VERSION 5.8 ;
DIVIDERCHAR "/" ;
BUSBITCHARS "[]" ;

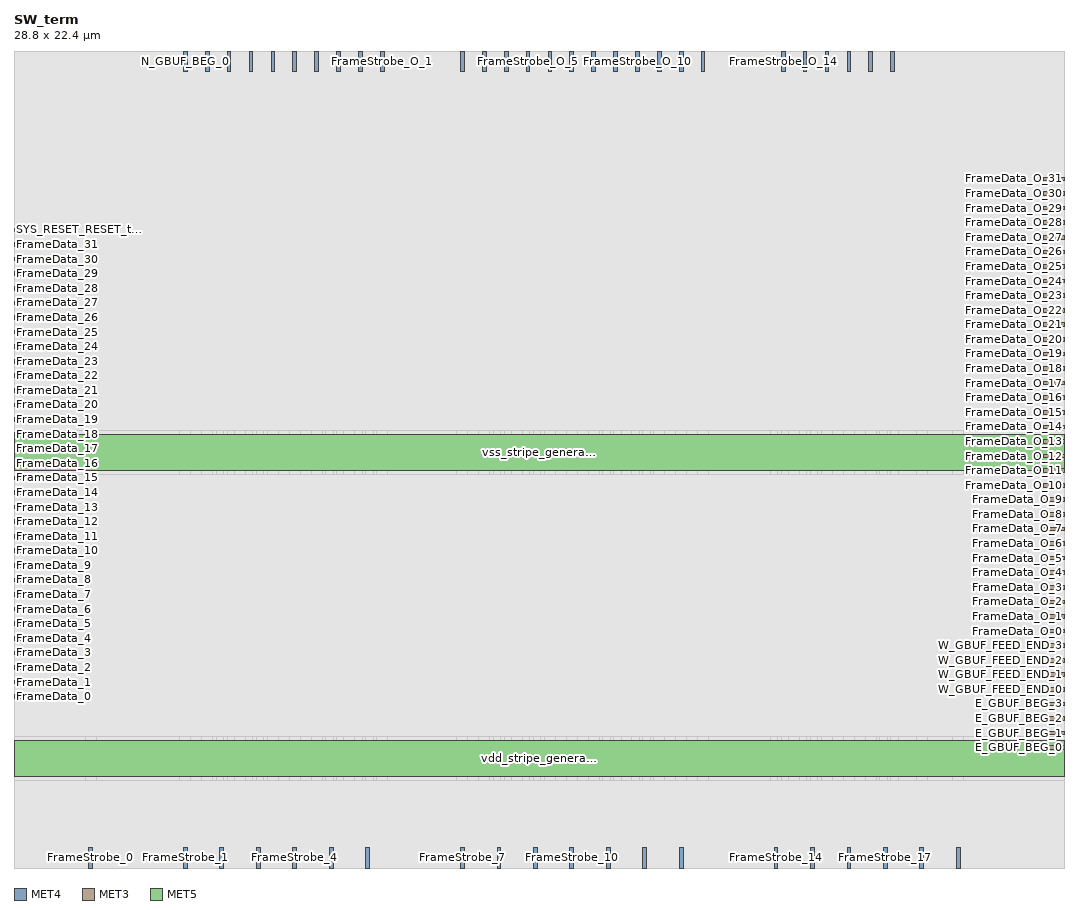
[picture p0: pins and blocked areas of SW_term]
MACRO SW_term
  CLASS BLOCK ;
  FOREIGN SW_term ;
  ORIGIN 0.0 0.0 ;
  SIZE 28.800 BY 22.400 ;
  SYMMETRY X Y ;
  PIN S_GBUF_FEED_END_0
    DIRECTION INPUT ;
    USE SIGNAL ;
    PORT
      LAYER MET4 ;
        RECT 7.050 21.850 7.150 22.400 ;
    END
  END S_GBUF_FEED_END_0
  PIN S_GBUF_FEED_END_1
    DIRECTION INPUT ;
    USE SIGNAL ;
    PORT
      LAYER MET4 ;
        RECT 7.650 21.850 7.750 22.400 ;
    END
  END S_GBUF_FEED_END_1
  PIN S_GBUF_FEED_END_2
    DIRECTION INPUT ;
    USE SIGNAL ;
    PORT
      LAYER MET4 ;
        RECT 8.250 21.850 8.350 22.400 ;
    END
  END S_GBUF_FEED_END_2
  PIN S_GBUF_FEED_END_3
    DIRECTION INPUT ;
    USE SIGNAL ;
    PORT
      LAYER MET4 ;
        RECT 8.850 21.850 8.950 22.400 ;
    END
  END S_GBUF_FEED_END_3
  PIN N_GBUF_BEG_0
    DIRECTION OUTPUT ;
    USE SIGNAL ;
    PORT
      LAYER MET4 ;
        RECT 4.650 21.850 4.750 22.400 ;
    END
  END N_GBUF_BEG_0
  PIN N_GBUF_BEG_1
    DIRECTION OUTPUT ;
    USE SIGNAL ;
    PORT
      LAYER MET4 ;
        RECT 5.250 21.850 5.350 22.400 ;
    END
  END N_GBUF_BEG_1
  PIN N_GBUF_BEG_2
    DIRECTION OUTPUT ;
    USE SIGNAL ;
    PORT
      LAYER MET4 ;
        RECT 5.850 21.850 5.950 22.400 ;
    END
  END N_GBUF_BEG_2
  PIN N_GBUF_BEG_3
    DIRECTION OUTPUT ;
    USE SIGNAL ;
    PORT
      LAYER MET4 ;
        RECT 6.450 21.850 6.550 22.400 ;
    END
  END N_GBUF_BEG_3
  PIN W_GBUF_FEED_END_0
    DIRECTION INPUT ;
    USE SIGNAL ;
    PORT
      LAYER MET3 ;
        RECT 28.250 4.850 28.800 4.950 ;
    END
  END W_GBUF_FEED_END_0
  PIN W_GBUF_FEED_END_1
    DIRECTION INPUT ;
    USE SIGNAL ;
    PORT
      LAYER MET3 ;
        RECT 28.250 5.250 28.800 5.350 ;
    END
  END W_GBUF_FEED_END_1
  PIN W_GBUF_FEED_END_2
    DIRECTION INPUT ;
    USE SIGNAL ;
    PORT
      LAYER MET3 ;
        RECT 28.250 5.650 28.800 5.750 ;
    END
  END W_GBUF_FEED_END_2
  PIN W_GBUF_FEED_END_3
    DIRECTION INPUT ;
    USE SIGNAL ;
    PORT
      LAYER MET3 ;
        RECT 28.250 6.050 28.800 6.150 ;
    END
  END W_GBUF_FEED_END_3
  PIN E_GBUF_BEG_0
    DIRECTION OUTPUT ;
    USE SIGNAL ;
    PORT
      LAYER MET3 ;
        RECT 28.250 3.250 28.800 3.350 ;
    END
  END E_GBUF_BEG_0
  PIN E_GBUF_BEG_1
    DIRECTION OUTPUT ;
    USE SIGNAL ;
    PORT
      LAYER MET3 ;
        RECT 28.250 3.650 28.800 3.750 ;
    END
  END E_GBUF_BEG_1
  PIN E_GBUF_BEG_2
    DIRECTION OUTPUT ;
    USE SIGNAL ;
    PORT
      LAYER MET3 ;
        RECT 28.250 4.050 28.800 4.150 ;
    END
  END E_GBUF_BEG_2
  PIN E_GBUF_BEG_3
    DIRECTION OUTPUT ;
    USE SIGNAL ;
    PORT
      LAYER MET3 ;
        RECT 28.250 4.450 28.800 4.550 ;
    END
  END E_GBUF_BEG_3
  PIN SYS_RESET_RESET_top
    DIRECTION INPUT ;
    USE SIGNAL ;
    PORT
      LAYER MET3 ;
        RECT 0.000 17.450 0.550 17.550 ;
    END
  END SYS_RESET_RESET_top
  PIN FrameData_0
    DIRECTION INPUT ;
    USE SIGNAL ;
    PORT
      LAYER MET3 ;
        RECT 0.000 4.650 0.550 4.750 ;
    END
  END FrameData_0
  PIN FrameData_1
    DIRECTION INPUT ;
    USE SIGNAL ;
    PORT
      LAYER MET3 ;
        RECT 0.000 5.050 0.550 5.150 ;
    END
  END FrameData_1
  PIN FrameData_2
    DIRECTION INPUT ;
    USE SIGNAL ;
    PORT
      LAYER MET3 ;
        RECT 0.000 5.450 0.550 5.550 ;
    END
  END FrameData_2
  PIN FrameData_3
    DIRECTION INPUT ;
    USE SIGNAL ;
    PORT
      LAYER MET3 ;
        RECT 0.000 5.850 0.550 5.950 ;
    END
  END FrameData_3
  PIN FrameData_4
    DIRECTION INPUT ;
    USE SIGNAL ;
    PORT
      LAYER MET3 ;
        RECT 0.000 6.250 0.550 6.350 ;
    END
  END FrameData_4
  PIN FrameData_5
    DIRECTION INPUT ;
    USE SIGNAL ;
    PORT
      LAYER MET3 ;
        RECT 0.000 6.650 0.550 6.750 ;
    END
  END FrameData_5
  PIN FrameData_6
    DIRECTION INPUT ;
    USE SIGNAL ;
    PORT
      LAYER MET3 ;
        RECT 0.000 7.050 0.550 7.150 ;
    END
  END FrameData_6
  PIN FrameData_7
    DIRECTION INPUT ;
    USE SIGNAL ;
    PORT
      LAYER MET3 ;
        RECT 0.000 7.450 0.550 7.550 ;
    END
  END FrameData_7
  PIN FrameData_8
    DIRECTION INPUT ;
    USE SIGNAL ;
    PORT
      LAYER MET3 ;
        RECT 0.000 7.850 0.550 7.950 ;
    END
  END FrameData_8
  PIN FrameData_9
    DIRECTION INPUT ;
    USE SIGNAL ;
    PORT
      LAYER MET3 ;
        RECT 0.000 8.250 0.550 8.350 ;
    END
  END FrameData_9
  PIN FrameData_10
    DIRECTION INPUT ;
    USE SIGNAL ;
    PORT
      LAYER MET3 ;
        RECT 0.000 8.650 0.550 8.750 ;
    END
  END FrameData_10
  PIN FrameData_11
    DIRECTION INPUT ;
    USE SIGNAL ;
    PORT
      LAYER MET3 ;
        RECT 0.000 9.050 0.550 9.150 ;
    END
  END FrameData_11
  PIN FrameData_12
    DIRECTION INPUT ;
    USE SIGNAL ;
    PORT
      LAYER MET3 ;
        RECT 0.000 9.450 0.550 9.550 ;
    END
  END FrameData_12
  PIN FrameData_13
    DIRECTION INPUT ;
    USE SIGNAL ;
    PORT
      LAYER MET3 ;
        RECT 0.000 9.850 0.550 9.950 ;
    END
  END FrameData_13
  PIN FrameData_14
    DIRECTION INPUT ;
    USE SIGNAL ;
    PORT
      LAYER MET3 ;
        RECT 0.000 10.250 0.550 10.350 ;
    END
  END FrameData_14
  PIN FrameData_15
    DIRECTION INPUT ;
    USE SIGNAL ;
    PORT
      LAYER MET3 ;
        RECT 0.000 10.650 0.550 10.750 ;
    END
  END FrameData_15
  PIN FrameData_16
    DIRECTION INPUT ;
    USE SIGNAL ;
    PORT
      LAYER MET3 ;
        RECT 0.000 11.050 0.550 11.150 ;
    END
  END FrameData_16
  PIN FrameData_17
    DIRECTION INPUT ;
    USE SIGNAL ;
    PORT
      LAYER MET3 ;
        RECT 0.000 11.450 0.550 11.550 ;
    END
  END FrameData_17
  PIN FrameData_18
    DIRECTION INPUT ;
    USE SIGNAL ;
    PORT
      LAYER MET3 ;
        RECT 0.000 11.850 0.550 11.950 ;
    END
  END FrameData_18
  PIN FrameData_19
    DIRECTION INPUT ;
    USE SIGNAL ;
    PORT
      LAYER MET3 ;
        RECT 0.000 12.250 0.550 12.350 ;
    END
  END FrameData_19
  PIN FrameData_20
    DIRECTION INPUT ;
    USE SIGNAL ;
    PORT
      LAYER MET3 ;
        RECT 0.000 12.650 0.550 12.750 ;
    END
  END FrameData_20
  PIN FrameData_21
    DIRECTION INPUT ;
    USE SIGNAL ;
    PORT
      LAYER MET3 ;
        RECT 0.000 13.050 0.550 13.150 ;
    END
  END FrameData_21
  PIN FrameData_22
    DIRECTION INPUT ;
    USE SIGNAL ;
    PORT
      LAYER MET3 ;
        RECT 0.000 13.450 0.550 13.550 ;
    END
  END FrameData_22
  PIN FrameData_23
    DIRECTION INPUT ;
    USE SIGNAL ;
    PORT
      LAYER MET3 ;
        RECT 0.000 13.850 0.550 13.950 ;
    END
  END FrameData_23
  PIN FrameData_24
    DIRECTION INPUT ;
    USE SIGNAL ;
    PORT
      LAYER MET3 ;
        RECT 0.000 14.250 0.550 14.350 ;
    END
  END FrameData_24
  PIN FrameData_25
    DIRECTION INPUT ;
    USE SIGNAL ;
    PORT
      LAYER MET3 ;
        RECT 0.000 14.650 0.550 14.750 ;
    END
  END FrameData_25
  PIN FrameData_26
    DIRECTION INPUT ;
    USE SIGNAL ;
    PORT
      LAYER MET3 ;
        RECT 0.000 15.050 0.550 15.150 ;
    END
  END FrameData_26
  PIN FrameData_27
    DIRECTION INPUT ;
    USE SIGNAL ;
    PORT
      LAYER MET3 ;
        RECT 0.000 15.450 0.550 15.550 ;
    END
  END FrameData_27
  PIN FrameData_28
    DIRECTION INPUT ;
    USE SIGNAL ;
    PORT
      LAYER MET3 ;
        RECT 0.000 15.850 0.550 15.950 ;
    END
  END FrameData_28
  PIN FrameData_29
    DIRECTION INPUT ;
    USE SIGNAL ;
    PORT
      LAYER MET3 ;
        RECT 0.000 16.250 0.550 16.350 ;
    END
  END FrameData_29
  PIN FrameData_30
    DIRECTION INPUT ;
    USE SIGNAL ;
    PORT
      LAYER MET3 ;
        RECT 0.000 16.650 0.550 16.750 ;
    END
  END FrameData_30
  PIN FrameData_31
    DIRECTION INPUT ;
    USE SIGNAL ;
    PORT
      LAYER MET3 ;
        RECT 0.000 17.050 0.550 17.150 ;
    END
  END FrameData_31
  PIN FrameData_O_0
    DIRECTION OUTPUT ;
    USE SIGNAL ;
    PORT
      LAYER MET3 ;
        RECT 28.250 6.450 28.800 6.550 ;
    END
  END FrameData_O_0
  PIN FrameData_O_1
    DIRECTION OUTPUT ;
    USE SIGNAL ;
    PORT
      LAYER MET3 ;
        RECT 28.250 6.850 28.800 6.950 ;
    END
  END FrameData_O_1
  PIN FrameData_O_2
    DIRECTION OUTPUT ;
    USE SIGNAL ;
    PORT
      LAYER MET3 ;
        RECT 28.250 7.250 28.800 7.350 ;
    END
  END FrameData_O_2
  PIN FrameData_O_3
    DIRECTION OUTPUT ;
    USE SIGNAL ;
    PORT
      LAYER MET3 ;
        RECT 28.250 7.650 28.800 7.750 ;
    END
  END FrameData_O_3
  PIN FrameData_O_4
    DIRECTION OUTPUT ;
    USE SIGNAL ;
    PORT
      LAYER MET3 ;
        RECT 28.250 8.050 28.800 8.150 ;
    END
  END FrameData_O_4
  PIN FrameData_O_5
    DIRECTION OUTPUT ;
    USE SIGNAL ;
    PORT
      LAYER MET3 ;
        RECT 28.250 8.450 28.800 8.550 ;
    END
  END FrameData_O_5
  PIN FrameData_O_6
    DIRECTION OUTPUT ;
    USE SIGNAL ;
    PORT
      LAYER MET3 ;
        RECT 28.250 8.850 28.800 8.950 ;
    END
  END FrameData_O_6
  PIN FrameData_O_7
    DIRECTION OUTPUT ;
    USE SIGNAL ;
    PORT
      LAYER MET3 ;
        RECT 28.250 9.250 28.800 9.350 ;
    END
  END FrameData_O_7
  PIN FrameData_O_8
    DIRECTION OUTPUT ;
    USE SIGNAL ;
    PORT
      LAYER MET3 ;
        RECT 28.250 9.650 28.800 9.750 ;
    END
  END FrameData_O_8
  PIN FrameData_O_9
    DIRECTION OUTPUT ;
    USE SIGNAL ;
    PORT
      LAYER MET3 ;
        RECT 28.250 10.050 28.800 10.150 ;
    END
  END FrameData_O_9
  PIN FrameData_O_10
    DIRECTION OUTPUT ;
    USE SIGNAL ;
    PORT
      LAYER MET3 ;
        RECT 28.250 10.450 28.800 10.550 ;
    END
  END FrameData_O_10
  PIN FrameData_O_11
    DIRECTION OUTPUT ;
    USE SIGNAL ;
    PORT
      LAYER MET3 ;
        RECT 28.250 10.850 28.800 10.950 ;
    END
  END FrameData_O_11
  PIN FrameData_O_12
    DIRECTION OUTPUT ;
    USE SIGNAL ;
    PORT
      LAYER MET3 ;
        RECT 28.250 11.250 28.800 11.350 ;
    END
  END FrameData_O_12
  PIN FrameData_O_13
    DIRECTION OUTPUT ;
    USE SIGNAL ;
    PORT
      LAYER MET3 ;
        RECT 28.250 11.650 28.800 11.750 ;
    END
  END FrameData_O_13
  PIN FrameData_O_14
    DIRECTION OUTPUT ;
    USE SIGNAL ;
    PORT
      LAYER MET3 ;
        RECT 28.250 12.050 28.800 12.150 ;
    END
  END FrameData_O_14
  PIN FrameData_O_15
    DIRECTION OUTPUT ;
    USE SIGNAL ;
    PORT
      LAYER MET3 ;
        RECT 28.250 12.450 28.800 12.550 ;
    END
  END FrameData_O_15
  PIN FrameData_O_16
    DIRECTION OUTPUT ;
    USE SIGNAL ;
    PORT
      LAYER MET3 ;
        RECT 28.250 12.850 28.800 12.950 ;
    END
  END FrameData_O_16
  PIN FrameData_O_17
    DIRECTION OUTPUT ;
    USE SIGNAL ;
    PORT
      LAYER MET3 ;
        RECT 28.250 13.250 28.800 13.350 ;
    END
  END FrameData_O_17
  PIN FrameData_O_18
    DIRECTION OUTPUT ;
    USE SIGNAL ;
    PORT
      LAYER MET3 ;
        RECT 28.250 13.650 28.800 13.750 ;
    END
  END FrameData_O_18
  PIN FrameData_O_19
    DIRECTION OUTPUT ;
    USE SIGNAL ;
    PORT
      LAYER MET3 ;
        RECT 28.250 14.050 28.800 14.150 ;
    END
  END FrameData_O_19
  PIN FrameData_O_20
    DIRECTION OUTPUT ;
    USE SIGNAL ;
    PORT
      LAYER MET3 ;
        RECT 28.250 14.450 28.800 14.550 ;
    END
  END FrameData_O_20
  PIN FrameData_O_21
    DIRECTION OUTPUT ;
    USE SIGNAL ;
    PORT
      LAYER MET3 ;
        RECT 28.250 14.850 28.800 14.950 ;
    END
  END FrameData_O_21
  PIN FrameData_O_22
    DIRECTION OUTPUT ;
    USE SIGNAL ;
    PORT
      LAYER MET3 ;
        RECT 28.250 15.250 28.800 15.350 ;
    END
  END FrameData_O_22
  PIN FrameData_O_23
    DIRECTION OUTPUT ;
    USE SIGNAL ;
    PORT
      LAYER MET3 ;
        RECT 28.250 15.650 28.800 15.750 ;
    END
  END FrameData_O_23
  PIN FrameData_O_24
    DIRECTION OUTPUT ;
    USE SIGNAL ;
    PORT
      LAYER MET3 ;
        RECT 28.250 16.050 28.800 16.150 ;
    END
  END FrameData_O_24
  PIN FrameData_O_25
    DIRECTION OUTPUT ;
    USE SIGNAL ;
    PORT
      LAYER MET3 ;
        RECT 28.250 16.450 28.800 16.550 ;
    END
  END FrameData_O_25
  PIN FrameData_O_26
    DIRECTION OUTPUT ;
    USE SIGNAL ;
    PORT
      LAYER MET3 ;
        RECT 28.250 16.850 28.800 16.950 ;
    END
  END FrameData_O_26
  PIN FrameData_O_27
    DIRECTION OUTPUT ;
    USE SIGNAL ;
    PORT
      LAYER MET3 ;
        RECT 28.250 17.250 28.800 17.350 ;
    END
  END FrameData_O_27
  PIN FrameData_O_28
    DIRECTION OUTPUT ;
    USE SIGNAL ;
    PORT
      LAYER MET3 ;
        RECT 28.250 17.650 28.800 17.750 ;
    END
  END FrameData_O_28
  PIN FrameData_O_29
    DIRECTION OUTPUT ;
    USE SIGNAL ;
    PORT
      LAYER MET3 ;
        RECT 28.250 18.050 28.800 18.150 ;
    END
  END FrameData_O_29
  PIN FrameData_O_30
    DIRECTION OUTPUT ;
    USE SIGNAL ;
    PORT
      LAYER MET3 ;
        RECT 28.250 18.450 28.800 18.550 ;
    END
  END FrameData_O_30
  PIN FrameData_O_31
    DIRECTION OUTPUT ;
    USE SIGNAL ;
    PORT
      LAYER MET3 ;
        RECT 28.250 18.850 28.800 18.950 ;
    END
  END FrameData_O_31
  PIN FrameStrobe_0
    DIRECTION INPUT ;
    USE SIGNAL ;
    PORT
      LAYER MET4 ;
        RECT 2.050 0.000 2.150 0.550 ;
    END
  END FrameStrobe_0
  PIN FrameStrobe_1
    DIRECTION INPUT ;
    USE SIGNAL ;
    PORT
      LAYER MET4 ;
        RECT 4.650 0.000 4.750 0.550 ;
    END
  END FrameStrobe_1
  PIN FrameStrobe_2
    DIRECTION INPUT ;
    USE SIGNAL ;
    PORT
      LAYER MET4 ;
        RECT 5.650 0.000 5.750 0.550 ;
    END
  END FrameStrobe_2
  PIN FrameStrobe_3
    DIRECTION INPUT ;
    USE SIGNAL ;
    PORT
      LAYER MET4 ;
        RECT 6.650 0.000 6.750 0.550 ;
    END
  END FrameStrobe_3
  PIN FrameStrobe_4
    DIRECTION INPUT ;
    USE SIGNAL ;
    PORT
      LAYER MET4 ;
        RECT 7.650 0.000 7.750 0.550 ;
    END
  END FrameStrobe_4
  PIN FrameStrobe_5
    DIRECTION INPUT ;
    USE SIGNAL ;
    PORT
      LAYER MET4 ;
        RECT 8.650 0.000 8.750 0.550 ;
    END
  END FrameStrobe_5
  PIN FrameStrobe_6
    DIRECTION INPUT ;
    USE SIGNAL ;
    PORT
      LAYER MET4 ;
        RECT 9.650 0.000 9.750 0.550 ;
    END
  END FrameStrobe_6
  PIN FrameStrobe_7
    DIRECTION INPUT ;
    USE SIGNAL ;
    PORT
      LAYER MET4 ;
        RECT 12.250 0.000 12.350 0.550 ;
    END
  END FrameStrobe_7
  PIN FrameStrobe_8
    DIRECTION INPUT ;
    USE SIGNAL ;
    PORT
      LAYER MET4 ;
        RECT 13.250 0.000 13.350 0.550 ;
    END
  END FrameStrobe_8
  PIN FrameStrobe_9
    DIRECTION INPUT ;
    USE SIGNAL ;
    PORT
      LAYER MET4 ;
        RECT 14.250 0.000 14.350 0.550 ;
    END
  END FrameStrobe_9
  PIN FrameStrobe_10
    DIRECTION INPUT ;
    USE SIGNAL ;
    PORT
      LAYER MET4 ;
        RECT 15.250 0.000 15.350 0.550 ;
    END
  END FrameStrobe_10
  PIN FrameStrobe_11
    DIRECTION INPUT ;
    USE SIGNAL ;
    PORT
      LAYER MET4 ;
        RECT 16.250 0.000 16.350 0.550 ;
    END
  END FrameStrobe_11
  PIN FrameStrobe_12
    DIRECTION INPUT ;
    USE SIGNAL ;
    PORT
      LAYER MET4 ;
        RECT 17.250 0.000 17.350 0.550 ;
    END
  END FrameStrobe_12
  PIN FrameStrobe_13
    DIRECTION INPUT ;
    USE SIGNAL ;
    PORT
      LAYER MET4 ;
        RECT 18.250 0.000 18.350 0.550 ;
    END
  END FrameStrobe_13
  PIN FrameStrobe_14
    DIRECTION INPUT ;
    USE SIGNAL ;
    PORT
      LAYER MET4 ;
        RECT 20.850 0.000 20.950 0.550 ;
    END
  END FrameStrobe_14
  PIN FrameStrobe_15
    DIRECTION INPUT ;
    USE SIGNAL ;
    PORT
      LAYER MET4 ;
        RECT 21.850 0.000 21.950 0.550 ;
    END
  END FrameStrobe_15
  PIN FrameStrobe_16
    DIRECTION INPUT ;
    USE SIGNAL ;
    PORT
      LAYER MET4 ;
        RECT 22.850 0.000 22.950 0.550 ;
    END
  END FrameStrobe_16
  PIN FrameStrobe_17
    DIRECTION INPUT ;
    USE SIGNAL ;
    PORT
      LAYER MET4 ;
        RECT 23.850 0.000 23.950 0.550 ;
    END
  END FrameStrobe_17
  PIN FrameStrobe_18
    DIRECTION INPUT ;
    USE SIGNAL ;
    PORT
      LAYER MET4 ;
        RECT 24.850 0.000 24.950 0.550 ;
    END
  END FrameStrobe_18
  PIN FrameStrobe_19
    DIRECTION INPUT ;
    USE SIGNAL ;
    PORT
      LAYER MET4 ;
        RECT 25.850 0.000 25.950 0.550 ;
    END
  END FrameStrobe_19
  PIN FrameStrobe_O_0
    DIRECTION OUTPUT ;
    USE SIGNAL ;
    PORT
      LAYER MET4 ;
        RECT 9.450 21.850 9.550 22.400 ;
    END
  END FrameStrobe_O_0
  PIN FrameStrobe_O_1
    DIRECTION OUTPUT ;
    USE SIGNAL ;
    PORT
      LAYER MET4 ;
        RECT 10.050 21.850 10.150 22.400 ;
    END
  END FrameStrobe_O_1
  PIN FrameStrobe_O_2
    DIRECTION OUTPUT ;
    USE SIGNAL ;
    PORT
      LAYER MET4 ;
        RECT 12.250 21.850 12.350 22.400 ;
    END
  END FrameStrobe_O_2
  PIN FrameStrobe_O_3
    DIRECTION OUTPUT ;
    USE SIGNAL ;
    PORT
      LAYER MET4 ;
        RECT 12.850 21.850 12.950 22.400 ;
    END
  END FrameStrobe_O_3
  PIN FrameStrobe_O_4
    DIRECTION OUTPUT ;
    USE SIGNAL ;
    PORT
      LAYER MET4 ;
        RECT 13.450 21.850 13.550 22.400 ;
    END
  END FrameStrobe_O_4
  PIN FrameStrobe_O_5
    DIRECTION OUTPUT ;
    USE SIGNAL ;
    PORT
      LAYER MET4 ;
        RECT 14.050 21.850 14.150 22.400 ;
    END
  END FrameStrobe_O_5
  PIN FrameStrobe_O_6
    DIRECTION OUTPUT ;
    USE SIGNAL ;
    PORT
      LAYER MET4 ;
        RECT 14.650 21.850 14.750 22.400 ;
    END
  END FrameStrobe_O_6
  PIN FrameStrobe_O_7
    DIRECTION OUTPUT ;
    USE SIGNAL ;
    PORT
      LAYER MET4 ;
        RECT 15.250 21.850 15.350 22.400 ;
    END
  END FrameStrobe_O_7
  PIN FrameStrobe_O_8
    DIRECTION OUTPUT ;
    USE SIGNAL ;
    PORT
      LAYER MET4 ;
        RECT 15.850 21.850 15.950 22.400 ;
    END
  END FrameStrobe_O_8
  PIN FrameStrobe_O_9
    DIRECTION OUTPUT ;
    USE SIGNAL ;
    PORT
      LAYER MET4 ;
        RECT 16.450 21.850 16.550 22.400 ;
    END
  END FrameStrobe_O_9
  PIN FrameStrobe_O_10
    DIRECTION OUTPUT ;
    USE SIGNAL ;
    PORT
      LAYER MET4 ;
        RECT 17.050 21.850 17.150 22.400 ;
    END
  END FrameStrobe_O_10
  PIN FrameStrobe_O_11
    DIRECTION OUTPUT ;
    USE SIGNAL ;
    PORT
      LAYER MET4 ;
        RECT 17.650 21.850 17.750 22.400 ;
    END
  END FrameStrobe_O_11
  PIN FrameStrobe_O_12
    DIRECTION OUTPUT ;
    USE SIGNAL ;
    PORT
      LAYER MET4 ;
        RECT 18.250 21.850 18.350 22.400 ;
    END
  END FrameStrobe_O_12
  PIN FrameStrobe_O_13
    DIRECTION OUTPUT ;
    USE SIGNAL ;
    PORT
      LAYER MET4 ;
        RECT 18.850 21.850 18.950 22.400 ;
    END
  END FrameStrobe_O_13
  PIN FrameStrobe_O_14
    DIRECTION OUTPUT ;
    USE SIGNAL ;
    PORT
      LAYER MET4 ;
        RECT 21.050 21.850 21.150 22.400 ;
    END
  END FrameStrobe_O_14
  PIN FrameStrobe_O_15
    DIRECTION OUTPUT ;
    USE SIGNAL ;
    PORT
      LAYER MET4 ;
        RECT 21.650 21.850 21.750 22.400 ;
    END
  END FrameStrobe_O_15
  PIN FrameStrobe_O_16
    DIRECTION OUTPUT ;
    USE SIGNAL ;
    PORT
      LAYER MET4 ;
        RECT 22.250 21.850 22.350 22.400 ;
    END
  END FrameStrobe_O_16
  PIN FrameStrobe_O_17
    DIRECTION OUTPUT ;
    USE SIGNAL ;
    PORT
      LAYER MET4 ;
        RECT 22.850 21.850 22.950 22.400 ;
    END
  END FrameStrobe_O_17
  PIN FrameStrobe_O_18
    DIRECTION OUTPUT ;
    USE SIGNAL ;
    PORT
      LAYER MET4 ;
        RECT 23.450 21.850 23.550 22.400 ;
    END
  END FrameStrobe_O_18
  PIN FrameStrobe_O_19
    DIRECTION OUTPUT ;
    USE SIGNAL ;
    PORT
      LAYER MET4 ;
        RECT 24.050 21.850 24.150 22.400 ;
    END
  END FrameStrobe_O_19
  PIN vdd_stripe_generate
    DIRECTION INOUT ;
    USE POWER ;
    PORT
      LAYER MET5 ;
        RECT 0.000 2.500 28.800 3.500 ;
    END
  END vdd_stripe_generate
  PIN vss_stripe_generate
    DIRECTION INOUT ;
    USE GROUND ;
    PORT
      LAYER MET5 ;
        RECT 0.000 10.900 28.800 11.900 ;
    END
  END vss_stripe_generate
  OBS
    LAYER MET1 ;
    RECT 0.000 0.000 28.800 22.400 ;
    LAYER MET2 ;
    RECT 0.000 0.000 28.800 22.400 ;
    LAYER MET3 ;
    RECT 0.000 0.000 28.800 3.150 ;
    LAYER MET3 ;
    RECT 0.000 3.150 28.150 3.450 ;
    LAYER MET3 ;
    RECT 0.000 3.450 28.800 3.550 ;
    LAYER MET3 ;
    RECT 0.000 3.550 28.150 3.850 ;
    LAYER MET3 ;
    RECT 0.000 3.850 28.800 3.950 ;
    LAYER MET3 ;
    RECT 0.000 3.950 28.150 4.250 ;
    LAYER MET3 ;
    RECT 0.000 4.250 28.800 4.350 ;
    LAYER MET3 ;
    RECT 0.000 4.350 28.150 4.550 ;
    LAYER MET3 ;
    RECT 0.650 4.550 28.150 4.650 ;
    LAYER MET3 ;
    RECT 0.650 4.650 28.800 4.750 ;
    LAYER MET3 ;
    RECT 0.650 4.750 28.150 4.850 ;
    LAYER MET3 ;
    RECT 0.000 4.850 28.150 4.950 ;
    LAYER MET3 ;
    RECT 0.650 4.950 28.150 5.050 ;
    LAYER MET3 ;
    RECT 0.650 5.050 28.800 5.150 ;
    LAYER MET3 ;
    RECT 0.650 5.150 28.150 5.250 ;
    LAYER MET3 ;
    RECT 0.000 5.250 28.150 5.350 ;
    LAYER MET3 ;
    RECT 0.650 5.350 28.150 5.450 ;
    LAYER MET3 ;
    RECT 0.650 5.450 28.800 5.550 ;
    LAYER MET3 ;
    RECT 0.650 5.550 28.150 5.650 ;
    LAYER MET3 ;
    RECT 0.000 5.650 28.150 5.750 ;
    LAYER MET3 ;
    RECT 0.650 5.750 28.150 5.850 ;
    LAYER MET3 ;
    RECT 0.650 5.850 28.800 5.950 ;
    LAYER MET3 ;
    RECT 0.650 5.950 28.150 6.050 ;
    LAYER MET3 ;
    RECT 0.000 6.050 28.150 6.150 ;
    LAYER MET3 ;
    RECT 0.650 6.150 28.150 6.250 ;
    LAYER MET3 ;
    RECT 0.650 6.250 28.800 6.350 ;
    LAYER MET3 ;
    RECT 0.650 6.350 28.150 6.450 ;
    LAYER MET3 ;
    RECT 0.000 6.450 28.150 6.550 ;
    LAYER MET3 ;
    RECT 0.650 6.550 28.150 6.650 ;
    LAYER MET3 ;
    RECT 0.650 6.650 28.800 6.750 ;
    LAYER MET3 ;
    RECT 0.650 6.750 28.150 6.850 ;
    LAYER MET3 ;
    RECT 0.000 6.850 28.150 6.950 ;
    LAYER MET3 ;
    RECT 0.650 6.950 28.150 7.050 ;
    LAYER MET3 ;
    RECT 0.650 7.050 28.800 7.150 ;
    LAYER MET3 ;
    RECT 0.650 7.150 28.150 7.250 ;
    LAYER MET3 ;
    RECT 0.000 7.250 28.150 7.350 ;
    LAYER MET3 ;
    RECT 0.650 7.350 28.150 7.450 ;
    LAYER MET3 ;
    RECT 0.650 7.450 28.800 7.550 ;
    LAYER MET3 ;
    RECT 0.650 7.550 28.150 7.650 ;
    LAYER MET3 ;
    RECT 0.000 7.650 28.150 7.750 ;
    LAYER MET3 ;
    RECT 0.650 7.750 28.150 7.850 ;
    LAYER MET3 ;
    RECT 0.650 7.850 28.800 7.950 ;
    LAYER MET3 ;
    RECT 0.650 7.950 28.150 8.050 ;
    LAYER MET3 ;
    RECT 0.000 8.050 28.150 8.150 ;
    LAYER MET3 ;
    RECT 0.650 8.150 28.150 8.250 ;
    LAYER MET3 ;
    RECT 0.650 8.250 28.800 8.350 ;
    LAYER MET3 ;
    RECT 0.650 8.350 28.150 8.450 ;
    LAYER MET3 ;
    RECT 0.000 8.450 28.150 8.550 ;
    LAYER MET3 ;
    RECT 0.650 8.550 28.150 8.650 ;
    LAYER MET3 ;
    RECT 0.650 8.650 28.800 8.750 ;
    LAYER MET3 ;
    RECT 0.650 8.750 28.150 8.850 ;
    LAYER MET3 ;
    RECT 0.000 8.850 28.150 8.950 ;
    LAYER MET3 ;
    RECT 0.650 8.950 28.150 9.050 ;
    LAYER MET3 ;
    RECT 0.650 9.050 28.800 9.150 ;
    LAYER MET3 ;
    RECT 0.650 9.150 28.150 9.250 ;
    LAYER MET3 ;
    RECT 0.000 9.250 28.150 9.350 ;
    LAYER MET3 ;
    RECT 0.650 9.350 28.150 9.450 ;
    LAYER MET3 ;
    RECT 0.650 9.450 28.800 9.550 ;
    LAYER MET3 ;
    RECT 0.650 9.550 28.150 9.650 ;
    LAYER MET3 ;
    RECT 0.000 9.650 28.150 9.750 ;
    LAYER MET3 ;
    RECT 0.650 9.750 28.150 9.850 ;
    LAYER MET3 ;
    RECT 0.650 9.850 28.800 9.950 ;
    LAYER MET3 ;
    RECT 0.650 9.950 28.150 10.050 ;
    LAYER MET3 ;
    RECT 0.000 10.050 28.150 10.150 ;
    LAYER MET3 ;
    RECT 0.650 10.150 28.150 10.250 ;
    LAYER MET3 ;
    RECT 0.650 10.250 28.800 10.350 ;
    LAYER MET3 ;
    RECT 0.650 10.350 28.150 10.450 ;
    LAYER MET3 ;
    RECT 0.000 10.450 28.150 10.550 ;
    LAYER MET3 ;
    RECT 0.650 10.550 28.150 10.650 ;
    LAYER MET3 ;
    RECT 0.650 10.650 28.800 10.750 ;
    LAYER MET3 ;
    RECT 0.650 10.750 28.150 10.850 ;
    LAYER MET3 ;
    RECT 0.000 10.850 28.150 10.950 ;
    LAYER MET3 ;
    RECT 0.650 10.950 28.150 11.050 ;
    LAYER MET3 ;
    RECT 0.650 11.050 28.800 11.150 ;
    LAYER MET3 ;
    RECT 0.650 11.150 28.150 11.250 ;
    LAYER MET3 ;
    RECT 0.000 11.250 28.150 11.350 ;
    LAYER MET3 ;
    RECT 0.650 11.350 28.150 11.450 ;
    LAYER MET3 ;
    RECT 0.650 11.450 28.800 11.550 ;
    LAYER MET3 ;
    RECT 0.650 11.550 28.150 11.650 ;
    LAYER MET3 ;
    RECT 0.000 11.650 28.150 11.750 ;
    LAYER MET3 ;
    RECT 0.650 11.750 28.150 11.850 ;
    LAYER MET3 ;
    RECT 0.650 11.850 28.800 11.950 ;
    LAYER MET3 ;
    RECT 0.650 11.950 28.150 12.050 ;
    LAYER MET3 ;
    RECT 0.000 12.050 28.150 12.150 ;
    LAYER MET3 ;
    RECT 0.650 12.150 28.150 12.250 ;
    LAYER MET3 ;
    RECT 0.650 12.250 28.800 12.350 ;
    LAYER MET3 ;
    RECT 0.650 12.350 28.150 12.450 ;
    LAYER MET3 ;
    RECT 0.000 12.450 28.150 12.550 ;
    LAYER MET3 ;
    RECT 0.650 12.550 28.150 12.650 ;
    LAYER MET3 ;
    RECT 0.650 12.650 28.800 12.750 ;
    LAYER MET3 ;
    RECT 0.650 12.750 28.150 12.850 ;
    LAYER MET3 ;
    RECT 0.000 12.850 28.150 12.950 ;
    LAYER MET3 ;
    RECT 0.650 12.950 28.150 13.050 ;
    LAYER MET3 ;
    RECT 0.650 13.050 28.800 13.150 ;
    LAYER MET3 ;
    RECT 0.650 13.150 28.150 13.250 ;
    LAYER MET3 ;
    RECT 0.000 13.250 28.150 13.350 ;
    LAYER MET3 ;
    RECT 0.650 13.350 28.150 13.450 ;
    LAYER MET3 ;
    RECT 0.650 13.450 28.800 13.550 ;
    LAYER MET3 ;
    RECT 0.650 13.550 28.150 13.650 ;
    LAYER MET3 ;
    RECT 0.000 13.650 28.150 13.750 ;
    LAYER MET3 ;
    RECT 0.650 13.750 28.150 13.850 ;
    LAYER MET3 ;
    RECT 0.650 13.850 28.800 13.950 ;
    LAYER MET3 ;
    RECT 0.650 13.950 28.150 14.050 ;
    LAYER MET3 ;
    RECT 0.000 14.050 28.150 14.150 ;
    LAYER MET3 ;
    RECT 0.650 14.150 28.150 14.250 ;
    LAYER MET3 ;
    RECT 0.650 14.250 28.800 14.350 ;
    LAYER MET3 ;
    RECT 0.650 14.350 28.150 14.450 ;
    LAYER MET3 ;
    RECT 0.000 14.450 28.150 14.550 ;
    LAYER MET3 ;
    RECT 0.650 14.550 28.150 14.650 ;
    LAYER MET3 ;
    RECT 0.650 14.650 28.800 14.750 ;
    LAYER MET3 ;
    RECT 0.650 14.750 28.150 14.850 ;
    LAYER MET3 ;
    RECT 0.000 14.850 28.150 14.950 ;
    LAYER MET3 ;
    RECT 0.650 14.950 28.150 15.050 ;
    LAYER MET3 ;
    RECT 0.650 15.050 28.800 15.150 ;
    LAYER MET3 ;
    RECT 0.650 15.150 28.150 15.250 ;
    LAYER MET3 ;
    RECT 0.000 15.250 28.150 15.350 ;
    LAYER MET3 ;
    RECT 0.650 15.350 28.150 15.450 ;
    LAYER MET3 ;
    RECT 0.650 15.450 28.800 15.550 ;
    LAYER MET3 ;
    RECT 0.650 15.550 28.150 15.650 ;
    LAYER MET3 ;
    RECT 0.000 15.650 28.150 15.750 ;
    LAYER MET3 ;
    RECT 0.650 15.750 28.150 15.850 ;
    LAYER MET3 ;
    RECT 0.650 15.850 28.800 15.950 ;
    LAYER MET3 ;
    RECT 0.650 15.950 28.150 16.050 ;
    LAYER MET3 ;
    RECT 0.000 16.050 28.150 16.150 ;
    LAYER MET3 ;
    RECT 0.650 16.150 28.150 16.250 ;
    LAYER MET3 ;
    RECT 0.650 16.250 28.800 16.350 ;
    LAYER MET3 ;
    RECT 0.650 16.350 28.150 16.450 ;
    LAYER MET3 ;
    RECT 0.000 16.450 28.150 16.550 ;
    LAYER MET3 ;
    RECT 0.650 16.550 28.150 16.650 ;
    LAYER MET3 ;
    RECT 0.650 16.650 28.800 16.750 ;
    LAYER MET3 ;
    RECT 0.650 16.750 28.150 16.850 ;
    LAYER MET3 ;
    RECT 0.000 16.850 28.150 16.950 ;
    LAYER MET3 ;
    RECT 0.650 16.950 28.150 17.050 ;
    LAYER MET3 ;
    RECT 0.650 17.050 28.800 17.150 ;
    LAYER MET3 ;
    RECT 0.650 17.150 28.150 17.250 ;
    LAYER MET3 ;
    RECT 0.000 17.250 28.150 17.350 ;
    LAYER MET3 ;
    RECT 0.650 17.350 28.150 17.450 ;
    LAYER MET3 ;
    RECT 0.650 17.450 28.800 17.550 ;
    LAYER MET3 ;
    RECT 0.650 17.550 28.150 17.650 ;
    LAYER MET3 ;
    RECT 0.000 17.650 28.150 17.850 ;
    LAYER MET3 ;
    RECT 0.000 17.850 28.800 17.950 ;
    LAYER MET3 ;
    RECT 0.000 17.950 28.150 18.250 ;
    LAYER MET3 ;
    RECT 0.000 18.250 28.800 18.350 ;
    LAYER MET3 ;
    RECT 0.000 18.350 28.150 18.650 ;
    LAYER MET3 ;
    RECT 0.000 18.650 28.800 18.750 ;
    LAYER MET3 ;
    RECT 0.000 18.750 28.150 19.050 ;
    LAYER MET3 ;
    RECT 0.000 19.050 28.800 22.400 ;
    LAYER MET4 ;
    RECT 0.000 0.000 1.950 22.400 ;
    LAYER MET4 ;
    RECT 1.950 0.650 2.250 22.400 ;
    LAYER MET4 ;
    RECT 2.250 0.000 4.550 22.400 ;
    LAYER MET4 ;
    RECT 4.550 0.650 4.850 21.750 ;
    LAYER MET4 ;
    RECT 4.850 0.000 5.150 22.400 ;
    LAYER MET4 ;
    RECT 5.150 0.000 5.450 21.750 ;
    LAYER MET4 ;
    RECT 5.450 0.000 5.550 22.400 ;
    LAYER MET4 ;
    RECT 5.550 0.650 5.750 22.400 ;
    LAYER MET4 ;
    RECT 5.750 0.650 5.850 21.750 ;
    LAYER MET4 ;
    RECT 5.850 0.000 6.050 21.750 ;
    LAYER MET4 ;
    RECT 6.050 0.000 6.350 22.400 ;
    LAYER MET4 ;
    RECT 6.350 0.000 6.550 21.750 ;
    LAYER MET4 ;
    RECT 6.550 0.650 6.650 21.750 ;
    LAYER MET4 ;
    RECT 6.650 0.650 6.850 22.400 ;
    LAYER MET4 ;
    RECT 6.850 0.000 6.950 22.400 ;
    LAYER MET4 ;
    RECT 6.950 0.000 7.250 21.750 ;
    LAYER MET4 ;
    RECT 7.250 0.000 7.550 22.400 ;
    LAYER MET4 ;
    RECT 7.550 0.650 7.850 21.750 ;
    LAYER MET4 ;
    RECT 7.850 0.000 8.150 22.400 ;
    LAYER MET4 ;
    RECT 8.150 0.000 8.450 21.750 ;
    LAYER MET4 ;
    RECT 8.450 0.000 8.550 22.400 ;
    LAYER MET4 ;
    RECT 8.550 0.650 8.750 22.400 ;
    LAYER MET4 ;
    RECT 8.750 0.650 8.850 21.750 ;
    LAYER MET4 ;
    RECT 8.850 0.000 9.050 21.750 ;
    LAYER MET4 ;
    RECT 9.050 0.000 9.350 22.400 ;
    LAYER MET4 ;
    RECT 9.350 0.000 9.550 21.750 ;
    LAYER MET4 ;
    RECT 9.550 0.650 9.650 21.750 ;
    LAYER MET4 ;
    RECT 9.650 0.650 9.850 22.400 ;
    LAYER MET4 ;
    RECT 9.850 0.000 9.950 22.400 ;
    LAYER MET4 ;
    RECT 9.950 0.000 10.250 21.750 ;
    LAYER MET4 ;
    RECT 10.250 0.000 12.150 22.400 ;
    LAYER MET4 ;
    RECT 12.150 0.650 12.450 21.750 ;
    LAYER MET4 ;
    RECT 12.450 0.000 12.750 22.400 ;
    LAYER MET4 ;
    RECT 12.750 0.000 13.050 21.750 ;
    LAYER MET4 ;
    RECT 13.050 0.000 13.150 22.400 ;
    LAYER MET4 ;
    RECT 13.150 0.650 13.350 22.400 ;
    LAYER MET4 ;
    RECT 13.350 0.650 13.450 21.750 ;
    LAYER MET4 ;
    RECT 13.450 0.000 13.650 21.750 ;
    LAYER MET4 ;
    RECT 13.650 0.000 13.950 22.400 ;
    LAYER MET4 ;
    RECT 13.950 0.000 14.150 21.750 ;
    LAYER MET4 ;
    RECT 14.150 0.650 14.250 21.750 ;
    LAYER MET4 ;
    RECT 14.250 0.650 14.450 22.400 ;
    LAYER MET4 ;
    RECT 14.450 0.000 14.550 22.400 ;
    LAYER MET4 ;
    RECT 14.550 0.000 14.850 21.750 ;
    LAYER MET4 ;
    RECT 14.850 0.000 15.150 22.400 ;
    LAYER MET4 ;
    RECT 15.150 0.650 15.450 21.750 ;
    LAYER MET4 ;
    RECT 15.450 0.000 15.750 22.400 ;
    LAYER MET4 ;
    RECT 15.750 0.000 16.050 21.750 ;
    LAYER MET4 ;
    RECT 16.050 0.000 16.150 22.400 ;
    LAYER MET4 ;
    RECT 16.150 0.650 16.350 22.400 ;
    LAYER MET4 ;
    RECT 16.350 0.650 16.450 21.750 ;
    LAYER MET4 ;
    RECT 16.450 0.000 16.650 21.750 ;
    LAYER MET4 ;
    RECT 16.650 0.000 16.950 22.400 ;
    LAYER MET4 ;
    RECT 16.950 0.000 17.150 21.750 ;
    LAYER MET4 ;
    RECT 17.150 0.650 17.250 21.750 ;
    LAYER MET4 ;
    RECT 17.250 0.650 17.450 22.400 ;
    LAYER MET4 ;
    RECT 17.450 0.000 17.550 22.400 ;
    LAYER MET4 ;
    RECT 17.550 0.000 17.850 21.750 ;
    LAYER MET4 ;
    RECT 17.850 0.000 18.150 22.400 ;
    LAYER MET4 ;
    RECT 18.150 0.650 18.450 21.750 ;
    LAYER MET4 ;
    RECT 18.450 0.000 18.750 22.400 ;
    LAYER MET4 ;
    RECT 18.750 0.000 19.050 21.750 ;
    LAYER MET4 ;
    RECT 19.050 0.000 20.750 22.400 ;
    LAYER MET4 ;
    RECT 20.750 0.650 20.950 22.400 ;
    LAYER MET4 ;
    RECT 20.950 0.650 21.050 21.750 ;
    LAYER MET4 ;
    RECT 21.050 0.000 21.250 21.750 ;
    LAYER MET4 ;
    RECT 21.250 0.000 21.550 22.400 ;
    LAYER MET4 ;
    RECT 21.550 0.000 21.750 21.750 ;
    LAYER MET4 ;
    RECT 21.750 0.650 21.850 21.750 ;
    LAYER MET4 ;
    RECT 21.850 0.650 22.050 22.400 ;
    LAYER MET4 ;
    RECT 22.050 0.000 22.150 22.400 ;
    LAYER MET4 ;
    RECT 22.150 0.000 22.450 21.750 ;
    LAYER MET4 ;
    RECT 22.450 0.000 22.750 22.400 ;
    LAYER MET4 ;
    RECT 22.750 0.650 23.050 21.750 ;
    LAYER MET4 ;
    RECT 23.050 0.000 23.350 22.400 ;
    LAYER MET4 ;
    RECT 23.350 0.000 23.650 21.750 ;
    LAYER MET4 ;
    RECT 23.650 0.000 23.750 22.400 ;
    LAYER MET4 ;
    RECT 23.750 0.650 23.950 22.400 ;
    LAYER MET4 ;
    RECT 23.950 0.650 24.050 21.750 ;
    LAYER MET4 ;
    RECT 24.050 0.000 24.250 21.750 ;
    LAYER MET4 ;
    RECT 24.250 0.000 24.750 22.400 ;
    LAYER MET4 ;
    RECT 24.750 0.650 25.050 22.400 ;
    LAYER MET4 ;
    RECT 25.050 0.000 25.750 22.400 ;
    LAYER MET4 ;
    RECT 25.750 0.650 26.050 22.400 ;
    LAYER MET4 ;
    RECT 26.050 0.000 28.800 22.400 ;
    LAYER MET5 ;
    RECT 0.000 0.000 28.800 2.400 ;
    LAYER MET5 ;
    RECT 0.000 3.600 28.800 10.800 ;
    LAYER MET5 ;
    RECT 0.000 12.000 28.800 22.400 ;
  END

END SW_term

END LIBRARY
